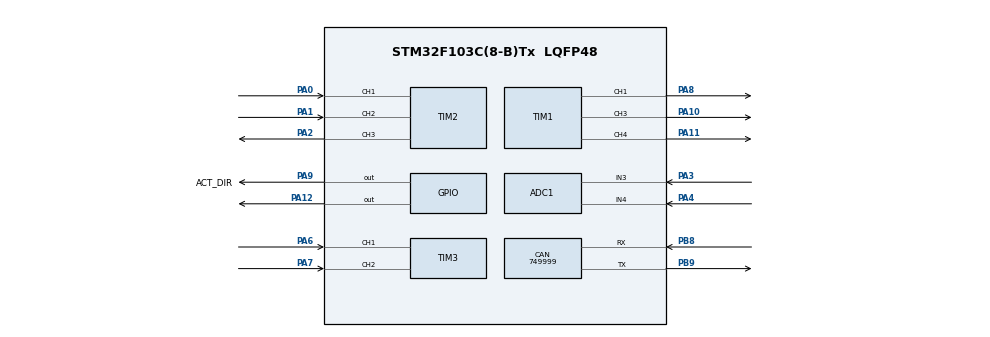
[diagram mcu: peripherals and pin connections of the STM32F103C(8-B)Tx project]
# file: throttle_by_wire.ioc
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ADC1.Channel-0\#ChannelRegularConversion=ADC_CHANNEL_4
ADC1.NbrOfConversionFlag=1
ADC1.Rank-0\#ChannelRegularConversion=1
ADC1.SamplingTime-0\#ChannelRegularConversion=ADC_SAMPLETIME_1CYCLE_5
ADC1.master=1
CAN.BS1=CAN_BS1_1TQ
CAN.BS2=CAN_BS2_1TQ
CAN.CalculateBaudRate=749999
CAN.CalculateTimeBit=1333
CAN.CalculateTimeQuantum=444.44444444444446
Mcu.Family=STM32F1
Mcu.Name=STM32F103C(8-B)Tx
Mcu.Package=LQFP48
NVIC.PriorityGroup=NVIC_PRIORITYGROUP_4
PA0-WKUP.Signal=S_TIM2_CH1_ETR
PA1.Signal=S_TIM2_CH2
PA10.Signal=S_TIM1_CH3
PA11.Signal=S_TIM1_CH4
PA12.Signal=GPIO_Output
PA13.Mode=Serial_Wire
PA13.Signal=SYS_JTMS-SWDIO
PA14.Mode=Serial_Wire
PA14.Signal=SYS_JTCK-SWCLK
PA2.Signal=S_TIM2_CH3
PA3.Signal=ADCx_IN3
PA4.Signal=ADCx_IN4
PA6.Signal=S_TIM3_CH1
PA7.Signal=S_TIM3_CH2
PA8.Signal=S_TIM1_CH1
PA9.GPIO_Label=ACT_DIR
PA9.Signal=GPIO_Output
PB8.Mode=CAN_Activate
PB8.Signal=CAN_RX
PB9.Mode=CAN_Activate
PB9.Signal=CAN_TX
PD0-OSC_IN.Mode=HSE-External-Oscillator
PD0-OSC_IN.Signal=RCC_OSC_IN
PD1-OSC_OUT.Mode=HSE-External-Oscillator
PD1-OSC_OUT.Signal=RCC_OSC_OUT
ProjectManager.HeapSize=0x200
ProjectManager.StackSize=0x400
ProjectManager.TargetToolchain=STM32CubeIDE
RCC.ADCPresc=RCC_ADCPCLK2_DIV6
RCC.AHBFreq_Value=72000000
RCC.APB1CLKDivider=RCC_HCLK_DIV2
RCC.APB1Freq_Value=36000000
RCC.APB1TimFreq_Value=72000000
RCC.APB2Freq_Value=72000000
RCC.APB2TimFreq_Value=72000000
RCC.HCLKFreq_Value=72000000
RCC.PLLMUL=RCC_PLL_MUL9
RCC.PLLSourceVirtual=RCC_PLLSOURCE_HSE
RCC.SYSCLKFreq_VALUE=72000000
RCC.SYSCLKSource=RCC_SYSCLKSOURCE_PLLCLK
RCC.USBFreq_Value=72000000
SH.ADCx_IN3.0=ADC1_IN3,IN3
SH.ADCx_IN4.0=ADC1_IN4,IN4
SH.S_TIM1_CH1.0=TIM1_CH1,PWM Generation1 CH1
SH.S_TIM1_CH3.0=TIM1_CH3,PWM Generation3 CH3
SH.S_TIM1_CH4.0=TIM1_CH4,PWM Generation4 CH4
SH.S_TIM2_CH1_ETR.0=TIM2_CH1,Encoder_Interface
SH.S_TIM2_CH2.0=TIM2_CH2,Encoder_Interface
SH.S_TIM2_CH3.0=TIM2_CH3,PWM Generation3 CH3
SH.S_TIM3_CH1.0=TIM3_CH1,Encoder_Interface
SH.S_TIM3_CH2.0=TIM3_CH2,Encoder_Interface
TIM1.Channel-PWM\ Generation1\ CH1=TIM_CHANNEL_1
TIM1.Channel-PWM\ Generation3\ CH3=TIM_CHANNEL_3
TIM1.Channel-PWM\ Generation4\ CH4=TIM_CHANNEL_4
TIM2.Channel-PWM\ Generation3\ CH3=TIM_CHANNEL_3
board=custom

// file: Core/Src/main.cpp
/* USER CODE BEGIN Header */
/**
  ******************************************************************************
  * @file           : main.c
  * @brief          : Main program body
  ******************************************************************************
  * @attention
  *
  * Copyright (c) 2024 STMicroelectronics.
  * All rights reserved.
  *
  * This software is licensed under terms that can be found in the LICENSE file
  * in the root directory of this software component.
  * If no LICENSE file comes with this software, it is provided AS-IS.
  *
  ******************************************************************************
  */
/* USER CODE END Header */
#include <main.hpp>
#include "throttle.hpp"
/* USER CODE END Includes */

ADC_HandleTypeDef hadc1;

CAN_HandleTypeDef hcan;

TIM_HandleTypeDef htim1;
TIM_HandleTypeDef htim2;
TIM_HandleTypeDef htim3;

void SystemClock_Config(void);
static void MX_GPIO_Init(void);
static void MX_ADC1_Init(void);
static void MX_CAN_Init(void);
static void MX_TIM2_Init(void);
static void MX_TIM3_Init(void);
static void MX_TIM1_Init(void);

int main(void)
{

  /* USER CODE BEGIN 1 */
	Throttle throttle;
  /* USER CODE END 1 */

  /* MCU Configuration--------------------------------------------------------*/

  /* Reset of all peripherals, Initializes the Flash interface and the Systick. */
  HAL_Init();

  /* Configure the system clock */
  SystemClock_Config();

  /* Initialize all configured peripherals */
  MX_GPIO_Init();
  MX_ADC1_Init();
  MX_CAN_Init();
  MX_TIM2_Init();
  MX_TIM3_Init();
  MX_TIM1_Init();

  /* Infinite loop */
  while (1)
  {
	  int throttleValue = throttle.readThrottle(); // Read analog value from throttle
	  HAL_Delay(10);

  }
}

void SystemClock_Config(void)
{
  RCC_OscInitTypeDef RCC_OscInitStruct = {0};
  RCC_ClkInitTypeDef RCC_ClkInitStruct = {0};
  RCC_PeriphCLKInitTypeDef PeriphClkInit = {0};

  /** Initializes the RCC Oscillators according to the specified parameters
  * in the RCC_OscInitTypeDef structure.
  */
  RCC_OscInitStruct.OscillatorType = RCC_OSCILLATORTYPE_HSI;
  RCC_OscInitStruct.HSIState = RCC_HSI_ON;
  RCC_OscInitStruct.HSICalibrationValue = RCC_HSICALIBRATION_DEFAULT;
  RCC_OscInitStruct.PLL.PLLState = RCC_PLL_NONE;
  if (HAL_RCC_OscConfig(&RCC_OscInitStruct) != HAL_OK)
  {
    Error_Handler();
  }

  /** Initializes the CPU, AHB and APB buses clocks
  */
  RCC_ClkInitStruct.ClockType = RCC_CLOCKTYPE_HCLK|RCC_CLOCKTYPE_SYSCLK
                              |RCC_CLOCKTYPE_PCLK1|RCC_CLOCKTYPE_PCLK2;
  RCC_ClkInitStruct.SYSCLKSource = RCC_SYSCLKSOURCE_HSI;
  RCC_ClkInitStruct.AHBCLKDivider = RCC_SYSCLK_DIV1;
  RCC_ClkInitStruct.APB1CLKDivider = RCC_HCLK_DIV1;
  RCC_ClkInitStruct.APB2CLKDivider = RCC_HCLK_DIV1;

  if (HAL_RCC_ClockConfig(&RCC_ClkInitStruct, FLASH_LATENCY_0) != HAL_OK)
  {
    Error_Handler();
  }
  PeriphClkInit.PeriphClockSelection = RCC_PERIPHCLK_ADC;
  PeriphClkInit.AdcClockSelection = RCC_ADCPCLK2_DIV2;
  if (HAL_RCCEx_PeriphCLKConfig(&PeriphClkInit) != HAL_OK)
  {
    Error_Handler();
  }
}

static void MX_ADC1_Init(void)
{

  ADC_ChannelConfTypeDef sConfig = {0};

  /** Common config
  */
  hadc1.Instance = ADC1;
  hadc1.Init.ScanConvMode = ADC_SCAN_DISABLE;
  hadc1.Init.ContinuousConvMode = DISABLE;
  hadc1.Init.DiscontinuousConvMode = DISABLE;
  hadc1.Init.ExternalTrigConv = ADC_SOFTWARE_START;
  hadc1.Init.DataAlign = ADC_DATAALIGN_RIGHT;
  hadc1.Init.NbrOfConversion = 1;
  if (HAL_ADC_Init(&hadc1) != HAL_OK)
  {
    Error_Handler();
  }

  /** Configure Regular Channel
  */
  sConfig.Channel = ADC_CHANNEL_4;
  sConfig.Rank = ADC_REGULAR_RANK_1;
  sConfig.SamplingTime = ADC_SAMPLETIME_1CYCLE_5;
  if (HAL_ADC_ConfigChannel(&hadc1, &sConfig) != HAL_OK)
  {
    Error_Handler();
  }

}

static void MX_CAN_Init(void)
{

  hcan.Instance = CAN1;
  hcan.Init.Prescaler = 16;
  hcan.Init.Mode = CAN_MODE_NORMAL;
  hcan.Init.SyncJumpWidth = CAN_SJW_1TQ;
  hcan.Init.TimeSeg1 = CAN_BS1_1TQ;
  hcan.Init.TimeSeg2 = CAN_BS2_1TQ;
  hcan.Init.TimeTriggeredMode = DISABLE;
  hcan.Init.AutoBusOff = DISABLE;
  hcan.Init.AutoWakeUp = DISABLE;
  hcan.Init.AutoRetransmission = DISABLE;
  hcan.Init.ReceiveFifoLocked = DISABLE;
  hcan.Init.TransmitFifoPriority = DISABLE;
  if (HAL_CAN_Init(&hcan) != HAL_OK)
  {
    Error_Handler();
  }

}

static void MX_TIM1_Init(void)
{

  TIM_MasterConfigTypeDef sMasterConfig = {0};
  TIM_OC_InitTypeDef sConfigOC = {0};
  TIM_BreakDeadTimeConfigTypeDef sBreakDeadTimeConfig = {0};

  htim1.Instance = TIM1;
  htim1.Init.Prescaler = 0;
  htim1.Init.CounterMode = TIM_COUNTERMODE_UP;
  htim1.Init.Period = 65535;
  htim1.Init.ClockDivision = TIM_CLOCKDIVISION_DIV1;
  htim1.Init.RepetitionCounter = 0;
  htim1.Init.AutoReloadPreload = TIM_AUTORELOAD_PRELOAD_DISABLE;
  if (HAL_TIM_PWM_Init(&htim1) != HAL_OK)
  {
    Error_Handler();
  }
  sMasterConfig.MasterOutputTrigger = TIM_TRGO_RESET;
  sMasterConfig.MasterSlaveMode = TIM_MASTERSLAVEMODE_DISABLE;
  if (HAL_TIMEx_MasterConfigSynchronization(&htim1, &sMasterConfig) != HAL_OK)
  {
    Error_Handler();
  }
  sConfigOC.OCMode = TIM_OCMODE_PWM1;
  sConfigOC.Pulse = 0;
  sConfigOC.OCPolarity = TIM_OCPOLARITY_HIGH;
  sConfigOC.OCNPolarity = TIM_OCNPOLARITY_HIGH;
  sConfigOC.OCFastMode = TIM_OCFAST_DISABLE;
  sConfigOC.OCIdleState = TIM_OCIDLESTATE_RESET;
  sConfigOC.OCNIdleState = TIM_OCNIDLESTATE_RESET;
  if (HAL_TIM_PWM_ConfigChannel(&htim1, &sConfigOC, TIM_CHANNEL_1) != HAL_OK)
  {
    Error_Handler();
  }
  if (HAL_TIM_PWM_ConfigChannel(&htim1, &sConfigOC, TIM_CHANNEL_3) != HAL_OK)
  {
    Error_Handler();
  }
  if (HAL_TIM_PWM_ConfigChannel(&htim1, &sConfigOC, TIM_CHANNEL_4) != HAL_OK)
  {
    Error_Handler();
  }
  sBreakDeadTimeConfig.OffStateRunMode = TIM_OSSR_DISABLE;
  sBreakDeadTimeConfig.OffStateIDLEMode = TIM_OSSI_DISABLE;
  sBreakDeadTimeConfig.LockLevel = TIM_LOCKLEVEL_OFF;
  sBreakDeadTimeConfig.DeadTime = 0;
  sBreakDeadTimeConfig.BreakState = TIM_BREAK_DISABLE;
  sBreakDeadTimeConfig.BreakPolarity = TIM_BREAKPOLARITY_HIGH;
  sBreakDeadTimeConfig.AutomaticOutput = TIM_AUTOMATICOUTPUT_DISABLE;
  if (HAL_TIMEx_ConfigBreakDeadTime(&htim1, &sBreakDeadTimeConfig) != HAL_OK)
  {
    Error_Handler();
  }
  HAL_TIM_MspPostInit(&htim1);

}

static void MX_TIM2_Init(void)
{

  TIM_Encoder_InitTypeDef sConfig = {0};
  TIM_MasterConfigTypeDef sMasterConfig = {0};
  TIM_OC_InitTypeDef sConfigOC = {0};

  htim2.Instance = TIM2;
  htim2.Init.Prescaler = 0;
  htim2.Init.CounterMode = TIM_COUNTERMODE_UP;
  htim2.Init.Period = 65535;
  htim2.Init.ClockDivision = TIM_CLOCKDIVISION_DIV1;
  htim2.Init.AutoReloadPreload = TIM_AUTORELOAD_PRELOAD_DISABLE;
  if (HAL_TIM_PWM_Init(&htim2) != HAL_OK)
  {
    Error_Handler();
  }
  sConfig.EncoderMode = TIM_ENCODERMODE_TI1;
  sConfig.IC1Polarity = TIM_ICPOLARITY_RISING;
  sConfig.IC1Selection = TIM_ICSELECTION_DIRECTTI;
  sConfig.IC1Prescaler = TIM_ICPSC_DIV1;
  sConfig.IC1Filter = 0;
  sConfig.IC2Polarity = TIM_ICPOLARITY_RISING;
  sConfig.IC2Selection = TIM_ICSELECTION_DIRECTTI;
  sConfig.IC2Prescaler = TIM_ICPSC_DIV1;
  sConfig.IC2Filter = 0;
  if (HAL_TIM_Encoder_Init(&htim2, &sConfig) != HAL_OK)
  {
    Error_Handler();
  }
  sMasterConfig.MasterOutputTrigger = TIM_TRGO_RESET;
  sMasterConfig.MasterSlaveMode = TIM_MASTERSLAVEMODE_DISABLE;
  if (HAL_TIMEx_MasterConfigSynchronization(&htim2, &sMasterConfig) != HAL_OK)
  {
    Error_Handler();
  }
  sConfigOC.OCMode = TIM_OCMODE_PWM1;
  sConfigOC.Pulse = 0;
  sConfigOC.OCPolarity = TIM_OCPOLARITY_HIGH;
  sConfigOC.OCFastMode = TIM_OCFAST_DISABLE;
  if (HAL_TIM_PWM_ConfigChannel(&htim2, &sConfigOC, TIM_CHANNEL_3) != HAL_OK)
  {
    Error_Handler();
  }
  HAL_TIM_MspPostInit(&htim2);

}

static void MX_TIM3_Init(void)
{

  TIM_Encoder_InitTypeDef sConfig = {0};
  TIM_MasterConfigTypeDef sMasterConfig = {0};

  htim3.Instance = TIM3;
  htim3.Init.Prescaler = 0;
  htim3.Init.CounterMode = TIM_COUNTERMODE_UP;
  htim3.Init.Period = 65535;
  htim3.Init.ClockDivision = TIM_CLOCKDIVISION_DIV1;
  htim3.Init.AutoReloadPreload = TIM_AUTORELOAD_PRELOAD_DISABLE;
  sConfig.EncoderMode = TIM_ENCODERMODE_TI1;
  sConfig.IC1Polarity = TIM_ICPOLARITY_RISING;
  sConfig.IC1Selection = TIM_ICSELECTION_DIRECTTI;
  sConfig.IC1Prescaler = TIM_ICPSC_DIV1;
  sConfig.IC1Filter = 0;
  sConfig.IC2Polarity = TIM_ICPOLARITY_RISING;
  sConfig.IC2Selection = TIM_ICSELECTION_DIRECTTI;
  sConfig.IC2Prescaler = TIM_ICPSC_DIV1;
  sConfig.IC2Filter = 0;
  if (HAL_TIM_Encoder_Init(&htim3, &sConfig) != HAL_OK)
  {
    Error_Handler();
  }
  sMasterConfig.MasterOutputTrigger = TIM_TRGO_RESET;
  sMasterConfig.MasterSlaveMode = TIM_MASTERSLAVEMODE_DISABLE;
  if (HAL_TIMEx_MasterConfigSynchronization(&htim3, &sMasterConfig) != HAL_OK)
  {
    Error_Handler();
  }

}

static void MX_GPIO_Init(void)
{
  GPIO_InitTypeDef GPIO_InitStruct = {0};

  /* GPIO Ports Clock Enable */
  __HAL_RCC_GPIOD_CLK_ENABLE();
  __HAL_RCC_GPIOA_CLK_ENABLE();
  __HAL_RCC_GPIOB_CLK_ENABLE();

  /*Configure GPIO pin Output Level */
  HAL_GPIO_WritePin(GPIOA, ACT_DIR_Pin|GPIO_PIN_12, GPIO_PIN_RESET);

  /*Configure GPIO pins : ACT_DIR_Pin PA12 */
  GPIO_InitStruct.Pin = ACT_DIR_Pin|GPIO_PIN_12;
  GPIO_InitStruct.Mode = GPIO_MODE_OUTPUT_PP;
  GPIO_InitStruct.Pull = GPIO_NOPULL;
  GPIO_InitStruct.Speed = GPIO_SPEED_FREQ_LOW;
  HAL_GPIO_Init(GPIOA, &GPIO_InitStruct);

}

void Error_Handler(void)
{
  __disable_irq();
  while (1)
  {
  }
}
